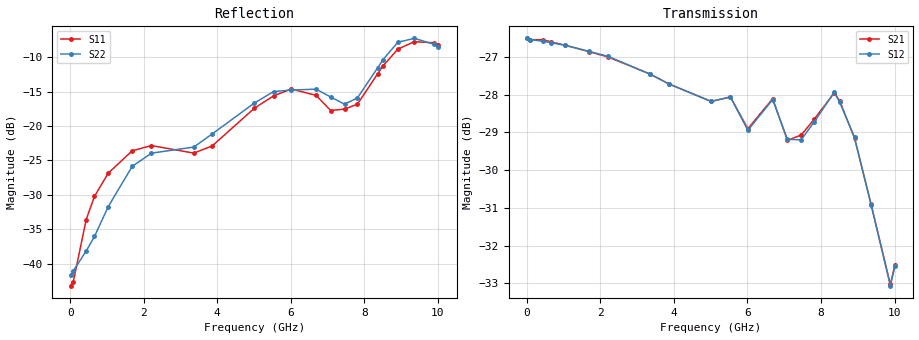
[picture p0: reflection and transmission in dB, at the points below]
! Device ID: PE43705
! Serial: 1
! Insertion: A
! Impedance: 50 ohm
! Temp: 25C
! VDD: 3.400V
! Attenuation Step: 25.50dB
#  Hz  S  RI  R  50
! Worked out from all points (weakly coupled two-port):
!   401 points, 10 MHz to 10.01 GHz, reference 50 ohm
!   highest |S21| = -26.51 dB at 10 MHz (marker M1); lowest = -33.0 dB at 9.885 GHz (marker M2)
!   lowest |S11| = -43.2 dB at 10 MHz (marker M3), VSWR 1.01, Z = 49.3 + j0.0456 ohm
!   |S11| at or under -10 dB: start of sweep to 8.69 GHz
!   |S22| runs from -41.7 to -7.2 dB; largest |S21 - S12| = 0.00064
!   S11 on the Smith chart (normalised r, x): 10 MHz: 0.99, +0.00; 7.46 GHz: 0.82, +0.16; 8.51 GHz: 0.82, +0.48; 9.36 GHz: 0.54, +0.48; 10.01 GHz: 0.48, +0.26
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1e7  -0.00693 0.000462  0.0473 -0.000183  0.0473 -0.000136  0.00825 0.000282
8.5e7  -0.00655 0.00353  0.0471 -0.00109  0.0471 -0.00112  0.0086 0.00232
4.35e8  -0.0117 0.0174  0.0468 -0.0054  0.0466 -0.00529  0.00344 0.0119
6.6e8  -0.0199 0.0236  0.0461 -0.00796  0.046 -0.00791  -0.00436 0.0152
1.035e9  -0.037 0.0265  0.0447 -0.0122  0.0447 -0.0121  -0.0216 0.0145
1.685e9  -0.064 0.0164  0.0414 -0.0187  0.0414 -0.0188  -0.0509 0.00201
2.21e9  -0.0721 0.00152  0.038 -0.0235  0.0381 -0.0235  -0.0627 -0.0102
3.36e9  -0.0635 0.00313  0.0287 -0.0312  0.0288 -0.0311  -0.0703 -0.00172
3.86e9  -0.0668 0.0259  0.0246 -0.033  0.0246 -0.033  -0.0858 0.0173
5.01e9  -0.1035 0.0861  0.0164 -0.0354  0.0164 -0.0354  -0.1285 0.0711
5.535e9  -0.133 0.0988  0.0122 -0.0376  0.0123 -0.0376  -0.1507 0.0945
6.01e9  -0.1561 0.1  0.00878 -0.0348  0.00889 -0.0346  -0.1506 0.1023
6.685e9  -0.147 0.079  0.00523 -0.039  0.00513 -0.0389  -0.1513 0.1067
7.085e9  -0.1141 0.0612  -0.00164 -0.0346  -0.00158 -0.0347  -0.114 0.1154
7.46e9  -0.0933 0.0943  -0.000589 -0.0352  -0.00059 -0.0347  -0.0718 0.1247
7.81e9  -0.049 0.1352  -0.00148 -0.0369  -0.00116 -0.0366  -0.041 0.1545
8.36e9  -0.0167 0.2382  -0.011 -0.0385  -0.011 -0.0386  -0.0182 0.2635
8.51e9  -0.0255 0.2723  -0.0139 -0.0365  -0.0137 -0.0364  -0.0233 0.3026
8.91e9  -0.0805 0.3518  -0.0178 -0.03  -0.0176 -0.0302  -0.0752 0.3981
9.36e9  -0.1808 0.3667  -0.0163 -0.0234  -0.0165 -0.0232  -0.1578 0.4023
9.885e9  -0.2969 0.2703  -0.00753 -0.021  -0.00755 -0.0209  -0.2752 0.2793
1.001e10  -0.3145 0.2281  -0.00559 -0.023  -0.00528 -0.023  -0.295 0.2285
